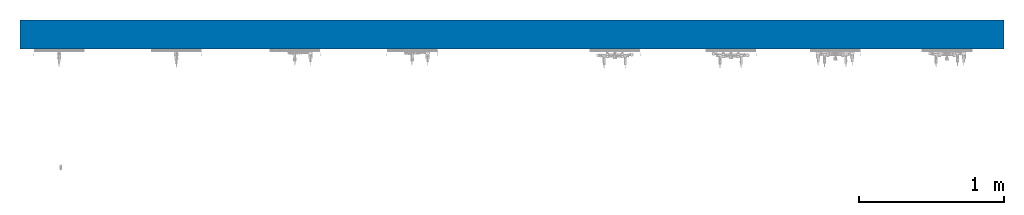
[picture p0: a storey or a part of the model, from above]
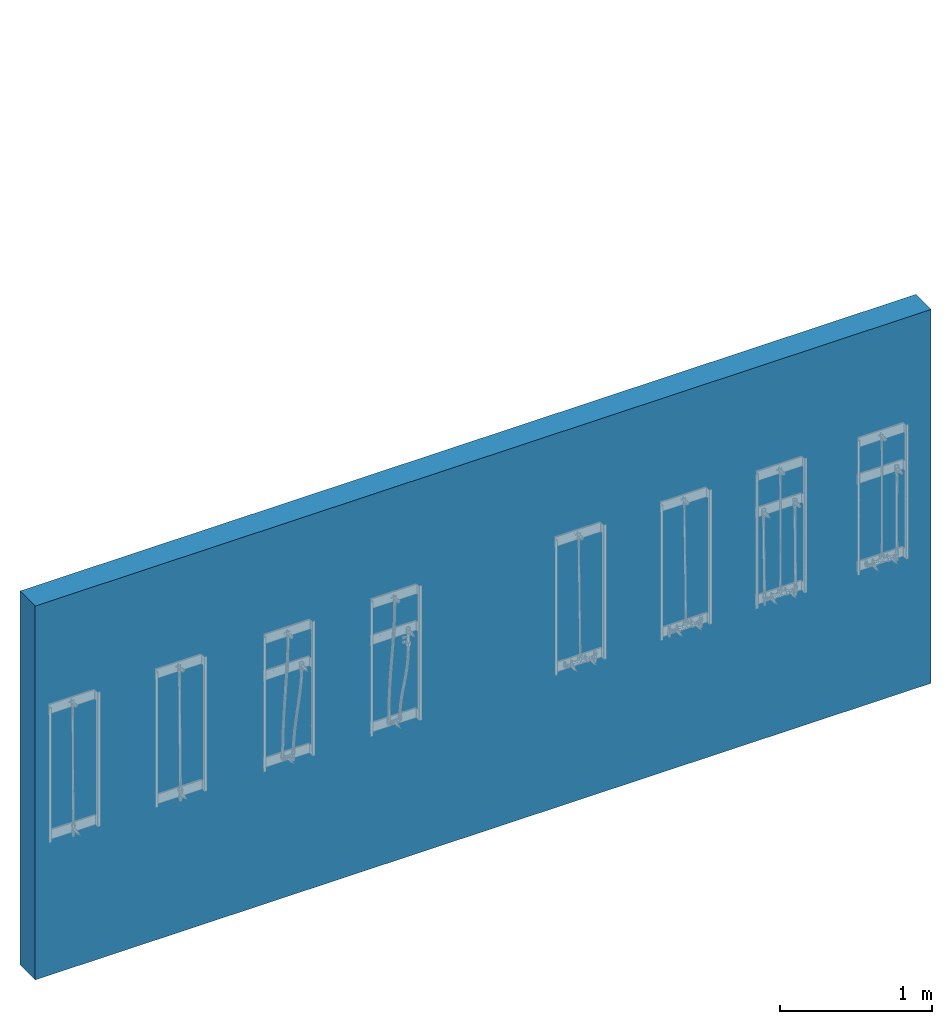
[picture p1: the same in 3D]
Properties of the parts of a building model (IFC2X3)

# File
Description: ViewDefinition [CoordinationView_V2.0]
File name: 0001
Time: 2025-09-23T14:31:26
Written by: The EXPRESS Data Manager Version 5.02.0100.07 : 28 Aug 2013
Made in: 21.0.0.383 - Exporter 21.0.0.383 - IU alternativa 21.0.0.383
Comment: STEP Physical File produced by: The EXPRESS Data Manager Version 5.02.0100.07 : 28 Aug 2013 * Module: EDMstepFileFactory/EDMstandAlone * Creation date: Tue Sep 23 14:31:26 2025 * Host: DNG1464 * Database: C:\Users\maria.cardoso\AppData\Local\Temp\034ea77f-56ce-4c5f-a24d-1eb75f36abe7\aeff3e23-a09a-4e3b-91bf-0d72654cbfd3\ifc * Database version: 5507 * Database creation date: Tue Sep 23 14:31:14 2025 * Schema: IFC2X3 * Model: DataRepository.ifc * Model creation date: Tue Sep 23 14:31:15 2025 * Header model: DataRepository.ifc_HeaderModel * Header model creation date: Tue Sep 23 14:31:15 2025 * EDMuser: sdai-user * EDMgroup: sdai-group * License ID and type: 5605 : Permanent license. Expiry date: * EDMstepFileFactory options: 020000

# IfcProject, 0001
LongName: Nome do projeto; Phase: Status do projeto

# IfcSite, Default
RefLatitude: -15, -52, 0, -120620; RefLongitude: -47, -55, 0, -114440; RefElevation: 0 mm

# IfcBuilding
Pset_BuildingCommon - NumberOfStoreys: 1

# IfcBuildingStorey: Nível:Cabeça de 8 mm, Nível 1
LongName: Nível 1; Elevation: 0 mm

# IfcDistributionPort (22)
Description: Flow
Name | FlowDirection
Port_357878 | SOURCEANDSINK | Group: Fornecimento hidrônico 4
Port_387485 | SOURCEANDSINK
Port_860569 | SOURCEANDSINK | Group: Fornecimento hidrônico 5
Port_862289 | SOURCEANDSINK | Group: Fornecimento hidrônico 29
Port_862289 | SOURCEANDSINK | Group: Fornecimento hidrônico 30
3 x Port_881773 | SOURCEANDSINK
2 x InPort_893381 | SOURCEANDSINK | Group: Fornecimento hidrônico 10
OutPort_893394 | SOURCEANDSINK | Group: Fornecimento hidrônico 10
OutPort_893384 | SOURCEANDSINK | Group: Fornecimento hidrônico 10
Port_893384 | SOURCEANDSINK | Group: Fornecimento hidrônico 10
Port_893394 | SOURCEANDSINK | Group: Fornecimento hidrônico 10
4 x Port_894468 | SOURCEANDSINK
2 x Port_915475 | SINK
2 x Port_961356 | SOURCEANDSINK

# IfcFlowFitting: Astra - Curva (Mola Curvadora):Astra - Curva (Mola Curvadora) (2)
In: Nível 1
Type - Material: Polietileno Reticulado - PEX
Type - Pset_DistributionFlowElementCommon - Reference: Astra - Curva (Mola Curvadora)
Type - Pset_ManufacturerTypeInformation - Manufacturer: Astra
Type - Pset_QuantityTakeOff - Reference: Astra - Curva (Mola Curvadora)
Pset_DistributionFlowElementCommon - sets with these values: 2
Group: Fornecimento hidrônico 10
Name (Astra - Curva (Mola Curvadora):Astra - Curva (Mola Curvadora):...)
893384
893394

# IfcFlowFitting: CHV01 - AF:Chassi Chuveiro 01 - AF, CHV01 - AF:Chassi Chuveiro 01 - AF:387485
In: Nível 1
Type - Material: Latão D
Type - Pset_DistributionFlowElementCommon - Reference: Chassi Chuveiro 01 - AF
Type - Pset_ManufacturerTypeInformation - Manufacturer: ASTRA
Type - Pset_QuantityTakeOff - Reference: Chassi Chuveiro 01 - AF
Material: Latão D, Latão, Polietileno de Resistencia à Temperatura - PERT, Material __RGBA_0.333_0.333_0.333_1.000
Pset_DistributionFlowElementCommon - sets with these values: 2

# IfcFlowFitting: CHV01 - AQ:Chassi Chuveiro 01 - AQ, CHV01 - AQ:Chassi Chuveiro 01 - AQ:881773
In: Nível 1
Type - Material: Latão D
Type - Pset_DistributionFlowElementCommon - Reference: Chassi Chuveiro 01 - AQ
Type - Pset_ManufacturerTypeInformation - Manufacturer: ASTRA
Type - Pset_QuantityTakeOff - Reference: Chassi Chuveiro 01 - AQ
Material: Latão D, Latão, PPR, Polietileno de Resistência à Temperatura - PERT AF, Polietileno de Resistência à Alta Temperatura - PERT, Material __RGBA_0.333_0.333_0.333_1.000
Pset_DistributionFlowElementCommon - sets with these values: 2

# IfcFlowFitting: CHV02 - AF:Chassi Chuveiro 02 - AF, CHV02 - AF:Chassi Chuveiro 02 - AF:357878
In: Nível 1
Type - Material: Latão D
Type - Pset_DistributionFlowElementCommon - Reference: Chassi Chuveiro 02 - AF
Type - Pset_ManufacturerTypeInformation - Manufacturer: ASTRA
Type - Pset_QuantityTakeOff - Reference: Chassi Chuveiro 02 - AF
Material: Latão D, Latão, Polietileno de Resistência à Temperatura - PERT, Material __RGBA_0.333_0.333_0.333_1.000; Group: Fornecimento hidrônico 4
Pset_DistributionFlowElementCommon - sets with these values: 2

# IfcFlowFitting: CHV02 - AQ:Chassi Chuveiro 02 - AQ, CHV02 - AQ:Chassi Chuveiro 02 - AQ:894468
In: Nível 1
Type - Material: Latão D
Type - Pset_DistributionFlowElementCommon - Reference: Chassi Chuveiro 02 - AQ
Type - Pset_ManufacturerTypeInformation - Manufacturer: ASTRA
Type - Pset_QuantityTakeOff - Reference: Chassi Chuveiro 02 - AQ
Material: Latão D, Latão, PPR, Polietileno de Resistência à Temperatura - PERT, Polietileno de Resistencia à Temperatura - PERT AQ, Material __RGBA_0.333_0.333_0.333_1.000
Pset_DistributionFlowElementCommon - sets with these values: 2

# IfcFlowFitting: CHV03 - AF:Chassi Chuveiro 03 - AF, CHV03 - AF:Chassi Chuveiro 03 - AF:860569
In: Nível 1
Type - Material: Latão D
Type - Pset_DistributionFlowElementCommon - Reference: Chassi Chuveiro 03 - AF
Type - Pset_ManufacturerTypeInformation - Manufacturer: ASTRA
Type - Pset_QuantityTakeOff - Reference: Chassi Chuveiro 03 - AF
Material: Latão D, Latão, Polietileno de Resistência à Temperatura - PERT AF, Material __RGBA_0.333_0.333_0.333_1.000; Group: Fornecimento hidrônico 5
Pset_DistributionFlowElementCommon - sets with these values: 2

# IfcFlowFitting: CHV03 - AQ:Chassi Chuveiro 03 - AQ, CHV03 - AQ:Chassi Chuveiro 03 - AQ:915475
In: Nível 1
Type - Material: Latão
Type - Pset_DistributionFlowElementCommon - Reference: Chassi Chuveiro 03 - AQ
Type - Pset_ManufacturerTypeInformation - Manufacturer: ASTRA
Type - Pset_QuantityTakeOff - Reference: Chassi Chuveiro 03 - AQ
Material: Latão, Latão D, PPR, Polietileno de Resistencia à Temperatura - PERT AQ, Polietileno de Resistencia à Temperatura - PERT AF, Material __RGBA_0.333_0.333_0.333_1.000
Pset_DistributionFlowElementCommon - sets with these values: 2

# IfcFlowFitting: CHV04 - AF:Chassi Chuveiro 04 - AF, CHV04 - AF:Chassi Chuveiro 04 - AF:862289
In: Nível 1
Type - Material: Latão D
Type - Pset_DistributionFlowElementCommon - Reference: Chassi Chuveiro 04 - AF
Type - Pset_ManufacturerTypeInformation - Manufacturer: ASTRA
Type - Pset_QuantityTakeOff - Reference: Chassi Chuveiro 04 - AF
Material: Latão D, Latão, Polietileno de Resistência à Temperatura - PERT AF, Material __RGBA_0.333_0.333_0.333_1.000; Group: Fornecimento hidrônico 30; Fornecimento hidrônico 29
Pset_DistributionFlowElementCommon - sets with these values: 2

# IfcFlowFitting: CHV04 - AQ:Chassi Chuveiro 04 - AQ, CHV04 - AQ:Chassi Chuveiro 04 - AQ:961356
In: Nível 1
Type - Material: Latão D
Type - Pset_DistributionFlowElementCommon - Reference: Chassi Chuveiro 04 - AQ
Type - Pset_ManufacturerTypeInformation - Manufacturer: ASTRA
Type - Pset_QuantityTakeOff - Reference: Chassi Chuveiro 04 - AQ
Material: Latão D, Latão, PPR, Polietileno de Resistência à Temperatura - PERT AF, Polietileno de Resistência à Temperatura - PERT AQ, Material __RGBA_0.333_0.333_0.333_1.000
Pset_DistributionFlowElementCommon - sets with these values: 2

# IfcFlowSegment: Tipos de tubos:Astra - PERT - Mola Curvadora AQ, Tipos de tubos:Astra - PERT - Mola Curvadora AQ:893381
In: Nível 1
Type - Pset_DistributionFlowElementCommon - Reference: Astra - PERT - Mola Curvadora AQ
Type - Pset_ManufacturerTypeInformation - Manufacturer: Astra
Type - Pset_QuantityTakeOff - Reference: Astra - PERT - Mola Curvadora AQ
Pset_DistributionFlowElementCommon - sets with these values: 2
Pset_FlowSegmentDuctSegment - Length: 21.7329 mm; sets with these values: 2
Group: Fornecimento hidrônico 10

# IfcWallStandardCase: Parede básica:Genérico - 200 mm, Parede básica:Genérico - 200 mm:1725884
In: Nível 1
Type - PredefinedType: STANDARD; Material: Material pré-definido de parede 200 mm
Type - Pset_QuantityTakeOff - Reference: Genérico - 200 mm
Type - Pset_ReinforcementBarPitchOfWall - Reference: Genérico - 200 mm
Type - Pset_WallCommon - Reference: Genérico - 200 mm; IsExternal: no
Pset_QuantityTakeOff - sets with these values: 2
Pset_WallCommon - IsExternal: yes; ExtendToStructure: no; LoadBearing: no
